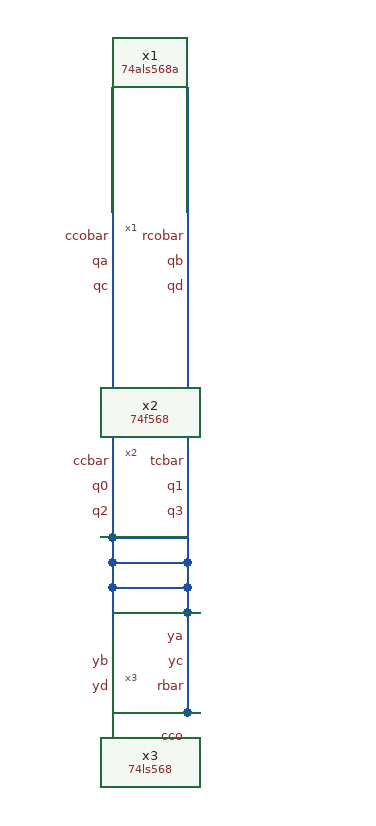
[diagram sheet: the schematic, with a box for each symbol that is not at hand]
v {xschem version=3.4.5 file_version=1.2}
G {}
K {}
V {}
S {}
E {}
C {74als568a.sym} 520 -300 0 0 {name=x1}
C {74f568.sym} 520 -120 0 0 {name=x2}
C {74ls568.sym} 520 60 0 0 {name=x3}
T {x1} 500 -280 0 0 0.25 0.25 {}
T {x2} 500 -100 0 0 0.25 0.25 {}
T {x3} 500 80 0 0 0.25 0.25 {}
N 490 -380 490 -200 {lab=gb}
N 490 -200 490 140 {lab=gb}
N 550 -380 550 -200 {lab=ub}
N 550 -200 550 40 {lab=ub}
N 490 -360 490 -180 {lab=clk}
N 490 -180 490 60 {lab=clk}
N 550 -360 550 -180 {lab=etbar}
N 550 -180 550 40 {lab=etbar}
N 550 40 490 40 {lab=etbar}
N 490 -340 490 -160 {lab=epbar}
N 490 -160 490 20 {lab=epbar}
N 490 20 550 20 {lab=epbar}
N 550 -340 550 -160 {lab=sclrb}
N 550 -160 550 120 {lab=sclrb}
N 490 -320 490 -140 {lab=loadb}
N 490 -140 490 -20 {lab=loadb}
N 550 -320 550 -140 {lab=mclrb}
N 550 -140 550 120 {lab=mclrb}
N 550 120 490 120 {lab=mclrb}
N 490 -300 490 -120 {lab=d0}
N 490 -120 490 -20 {lab=d0}
N 490 -20 550 -20 {lab=d0}
N 550 -300 550 -120 {lab=d1}
N 550 -120 550 0 {lab=d1}
N 550 0 490 0 {lab=d1}
N 490 -280 490 -100 {lab=d2}
N 490 -100 490 0 {lab=d2}
N 490 0 550 0 {lab=d2}
N 550 -280 550 -100 {lab=d3}
N 550 -100 550 20 {lab=d3}
N 550 20 490 20 {lab=d3}
C {devices/lab_pin.sym} 490 -260 0 0 {name=l_ccobar sig_type=std_logic lab=ccobar}
C {devices/lab_pin.sym} 550 -260 0 0 {name=l_rcobar sig_type=std_logic lab=rcobar}
C {devices/lab_pin.sym} 490 -240 0 0 {name=l_qa sig_type=std_logic lab=qa}
C {devices/lab_pin.sym} 550 -240 0 0 {name=l_qb sig_type=std_logic lab=qb}
C {devices/lab_pin.sym} 490 -220 0 0 {name=l_qc sig_type=std_logic lab=qc}
C {devices/lab_pin.sym} 550 -220 0 0 {name=l_qd sig_type=std_logic lab=qd}
C {devices/lab_pin.sym} 490 -80 0 0 {name=l_ccbar sig_type=std_logic lab=ccbar}
C {devices/lab_pin.sym} 550 -80 0 0 {name=l_tcbar sig_type=std_logic lab=tcbar}
C {devices/lab_pin.sym} 490 -60 0 0 {name=l_q0 sig_type=std_logic lab=q0}
C {devices/lab_pin.sym} 550 -60 0 0 {name=l_q1 sig_type=std_logic lab=q1}
C {devices/lab_pin.sym} 490 -40 0 0 {name=l_q2 sig_type=std_logic lab=q2}
C {devices/lab_pin.sym} 550 -40 0 0 {name=l_q3 sig_type=std_logic lab=q3}
C {devices/lab_pin.sym} 550 60 0 0 {name=l_ya sig_type=std_logic lab=ya}
C {devices/lab_pin.sym} 490 80 0 0 {name=l_yb sig_type=std_logic lab=yb}
C {devices/lab_pin.sym} 550 80 0 0 {name=l_yc sig_type=std_logic lab=yc}
C {devices/lab_pin.sym} 490 100 0 0 {name=l_yd sig_type=std_logic lab=yd}
C {devices/lab_pin.sym} 550 100 0 0 {name=l_rbar sig_type=std_logic lab=rbar}
C {devices/lab_pin.sym} 550 140 0 0 {name=l_cco sig_type=std_logic lab=cco}
